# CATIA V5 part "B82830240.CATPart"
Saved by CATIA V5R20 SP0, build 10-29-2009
Part number: B82830240
Revision: 5
Definition: design
Nomenclature: B82830240
Source: made
Description: NOT SPECIFIED
Bounding box of the stored display mesh (mm): x -17.817 to 17.817, y -18 to 18, z 0 to 240
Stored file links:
  C:\Users\Raffaele\Desktop\3D X SITO CF\BOLEX\7-PILLAR REF 828\B82830240.CATPart

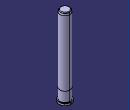
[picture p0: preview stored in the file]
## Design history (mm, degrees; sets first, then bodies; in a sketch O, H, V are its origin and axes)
Body1 "MANIFOLD_SOLID_BREP #450" (main body)
  Solid1: solid without history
